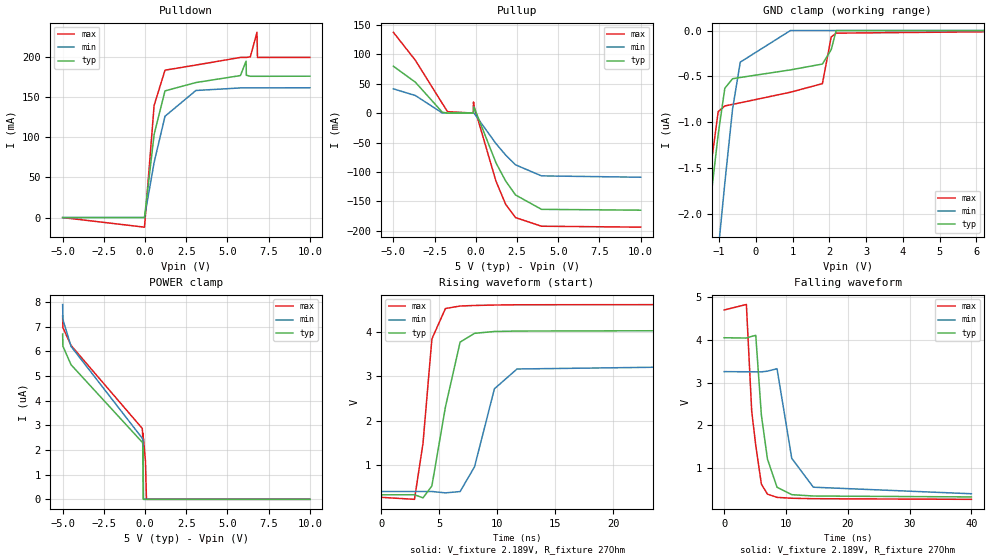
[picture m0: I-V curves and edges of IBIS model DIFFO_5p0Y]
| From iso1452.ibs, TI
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|   DIFFO_5p0Y Model
[Model]   DIFFO_5p0Y
Model_type   3-state
Polarity   Non-Inverting
Vmeas = 2.18852
Vref = 2.18852
Cref = 2pF
Rref = 27
|   typ   min   max
C_comp   25.098pF   24.414pF   25.214pF
|  Where Nom  PVT is Nominal Process, 5.0V,   27C
|   Fast PVT is Strong Process,  5.5V,   -40C
|   Slow PVT is Weak Process,   4.5V,   150C
[Voltage Range]   5   4.5   5.5
|Junction Temperature
[Temperature Range]   27   150   -40
[Pullup Reference]   5   4.5   5.5
[Pulldown Reference]   -0   -0   0
[Power Clamp Reference]   5   4.5   5.5
[GND Clamp Reference]   0   0   0
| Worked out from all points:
|   slope of the pulldown table from 0 to 0.75 V, typ, clamps not added: 5.76 ohm
|   slope of the pullup table from 0 to 0.75 V, typ, clamps not added: 13.7 ohm
|   falling waveform, V_fixture 2.189V, R_fixture 27Ohm: 20-80 % time 1.74ns typ, 2.43ns min, 1.49ns max; typ from 4.04 V to 0.337 V
|   rising waveform, V_fixture 2.189V, R_fixture 27Ohm: 20-80 % time 1.23ns typ, 1.65ns min, 910ps max; typ from 0.338 V to 4.03 V
[Pulldown]
|   Voltage   I(typ)   I(min)   I(max)
-5V       -2.768nA   -62.36nA   -404.6pA
-35mV     425.7nA    561.8nA    -11.95mA
550mV     103.6mA    68.78mA    139.8mA
1.21V     157.9mA    126.3mA    183.7mA
3.085V    168.3mA    158.4mA    190.1mA
5.785V    177mA      161.6mA    199.6mA
6.13V     195mA      161.6mA    199.6mA
6.145V    177.4mA    161.6mA    199.6mA
6.385V    176.1mA    161.6mA    200.3mA
6.79V     176.1mA    161.7mA    230.9mA
6.82V     176.1mA    161.7mA    199.6mA
10V       176.2mA    161.8mA    199.6mA
[GND Clamp]
|   Voltage   I(typ)   I(min)   I(max)
-5V       -16.78uA   -20.83uA   -17.26uA
-1.595V   -3.188uA   -4.867uA   -2.896uA
-1.235V   -1.86uA    -3.297uA   -1.512uA
-1.025V   -1.13uA    -2.4uA     -883.3nA
-845mV    -629.1nA   -1.663uA   -821.7nA
-635mV    -525.4nA   -857.6nA   -804.5nA
-425mV    -511.6nA   -344.6nA   -787.4nA
940mV     -428.9nA   0A         -672.2nA
1.81V     -365.2nA   0A         -578.8nA
2.05V     -208.4nA   0A         -69.8nA
2.185V    0A         0A         -28.58nA
10V       0A         0A         0A
[Pullup]
|   Voltage   I(typ)   I(min)   I(max)
-5V       79.85mA    41.35mA    137.6mA
-3.665V   52.62mA    30mA       89.9mA
-2.03V    1.545mA    178.1uA    16.37mA
-1.715V   102.2uA    92.32uA    2.543mA
-155mV    86.47uA    72.78uA    97.97uA
-140mV    85.13uA    71.46uA    19mA
-110mV    10.38mA    68.93uA    12.14mA
1.225V    -84.67mA   -51.91mA   -116mA
1.81V     -115.5mA   -71.3mA    -155.1mA
2.41V     -139.3mA   -88mA      -177.8mA
3.985V    -163.8mA   -106.8mA   -192.5mA
10V       -165.2mA   -109.1mA   -194.1mA
[POWER Clamp]
|   Voltage   I(typ)   I(min)   I(max)
-5V       6.707uA    7.907uA    7.452uA
-4.985V   6.207uA    7.35uA     6.964uA
-4.955V   6.17uA     7.231uA    6.927uA
-4.49V    5.462uA    6.208uA    6.245uA
-170mV    2.316uA    2.479uA    2.877uA
-140mV    2.258uA    2.42uA     2.558uA
-125mV    1.129uA    2.383uA    2.672uA
-110mV    0A         1.192uA    1.651uA
-95mV     0A         0A         2.474uA
25mV      0A         0A         1.541uA
85mV      0A         0A         0A
10V       0A         0A         0A
[Ramp]
R_load = 27
|   typ   min   max
dV/dt_r   2.21565/1.2197e-09   1.70608/1.64506e-09   2.59745/9.08801e-10
dV/dt_f   2.22324/1.72631e-09   1.70588/2.42465e-09   2.64478/1.49183e-09
[Falling Waveform]
V_fixture = 2.189V
V_fixture_min = 1.832V
V_fixture_max = 2.483V
R_fixture = 27Ohm
C_fixture = 0F
|   Time   V(typ)   V(min)   V(max)
0s        4.043V     3.254V     4.689V
3.599ns   4.036V     3.251V     4.817V
4.462ns   4.075V     3.251V     2.329V
5.116ns   4.098V     3.25V      1.536V
6.025ns   2.243V     3.249V     635.3mV
7.009ns   1.218V     3.265V     401.5mV
8.556ns   563mV      3.323V     326.7mV
10.94ns   389.4mV    1.235V     306.5mV
14.43ns   358.2mV    563.2mV    295.5mV
40ns      337.1mV    410.9mV    281mV
[Rising Waveform]
V_fixture = 2.189V
V_fixture_min = 1.832V
V_fixture_max = 2.483V
R_fixture = 27Ohm
C_fixture = 0F
|   Time   V(typ)   V(min)   V(max)
0s        337.7mV    412.1mV    281mV
2.883ns   339.6mV    412.4mV    236.3mV
3.618ns   269.6mV    412.5mV    1.494V
4.383ns   536.3mV    412.6mV    3.837V
5.55ns    2.308V     381.3mV    4.52V
6.816ns   3.765V     411mV      4.576V
8.061ns   3.963V     967.7mV    4.588V
9.774ns   4.004V     2.718V     4.598V
11.72ns   4.014V     3.162V     4.604V
40ns      4.03V      3.256V     4.61V
